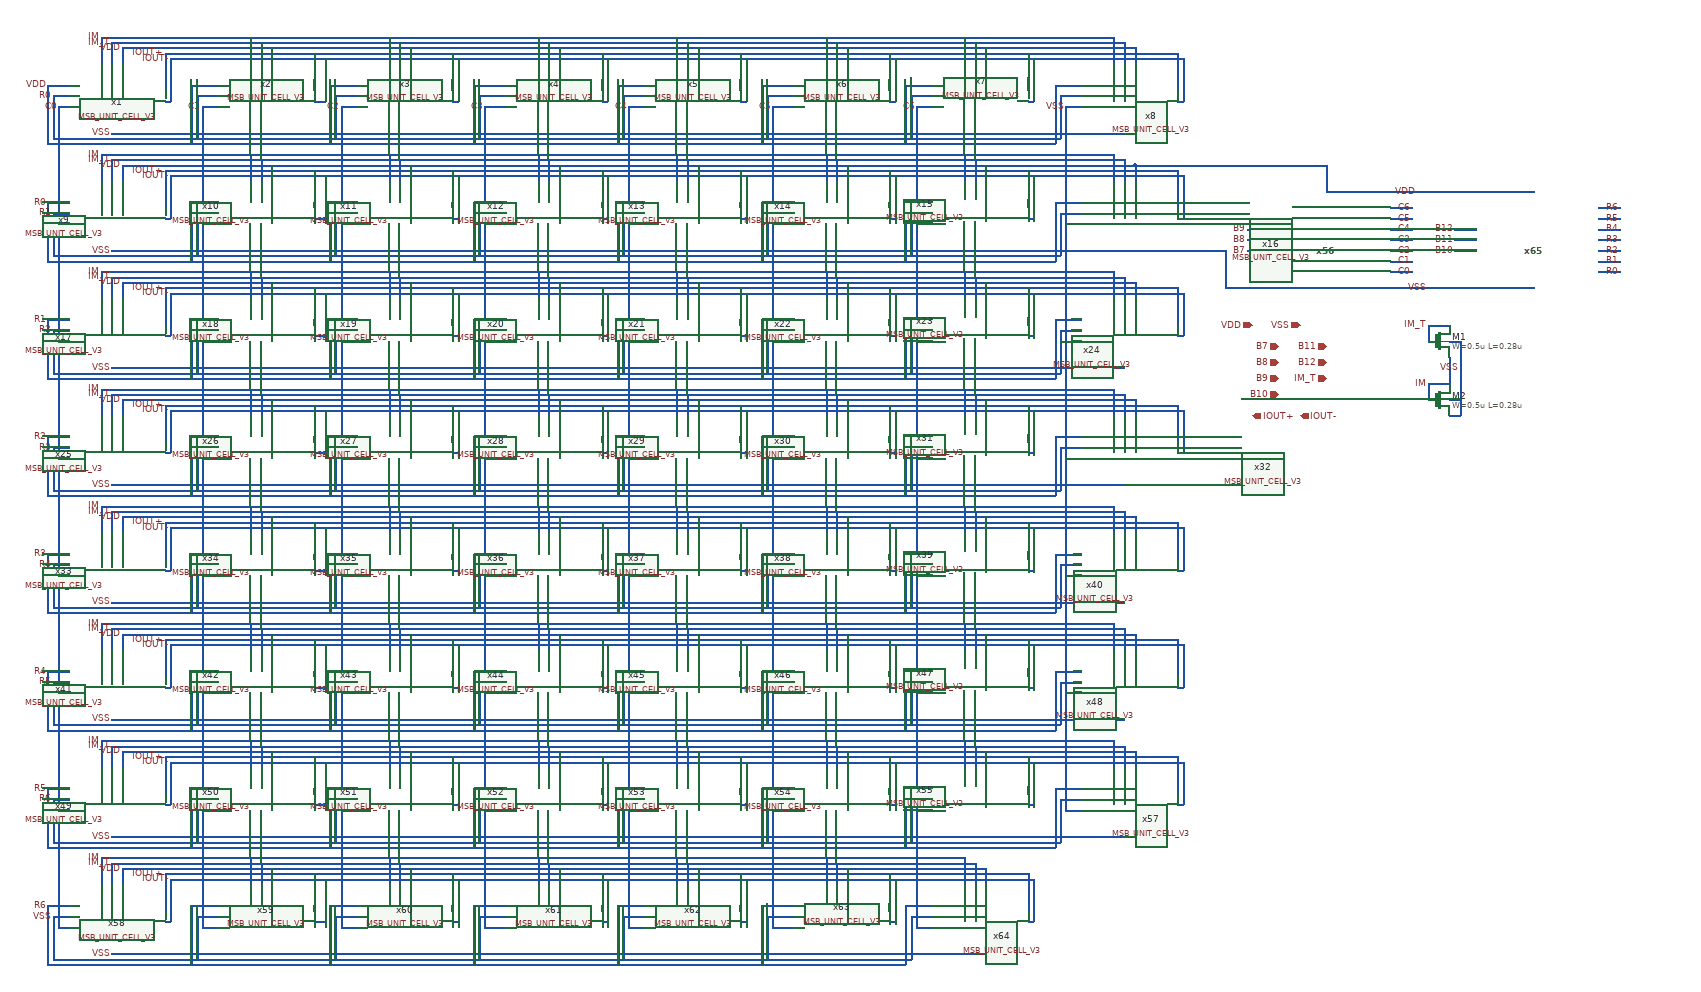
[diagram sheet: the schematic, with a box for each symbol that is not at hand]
v {xschem version=3.1.0 file_version=1.2
}
G {}
K {}
V {}
S {}
E {}
N 210 -1780 210 -1730 {
lab=IM}
N 210 -1780 2110 -1780 {
lab=IM}
N 2110 -1780 2110 -1730 {
lab=IM}
N 2130 -1770 2130 -1730 {
lab=IM_T}
N 2120 -1770 2130 -1770 {
lab=IM_T}
N 230 -1770 2120 -1770 {
lab=IM_T}
N 230 -1770 230 -1730 {
lab=IM_T}
N 250 -1760 250 -1730 {
lab=VDD}
N 250 -1760 2150 -1760 {
lab=VDD}
N 2150 -1760 2150 -1730 {
lab=VDD}
N 2230 -1750 2230 -1680 {
lab=IOUT+}
N 330 -1750 2230 -1750 {
lab=IOUT+}
N 330 -1750 330 -1680 {
lab=IOUT+}
N 330 -1660 340 -1660 {
lab=IOUT-}
N 340 -1740 340 -1660 {
lab=IOUT-}
N 340 -1740 2240 -1740 {
lab=IOUT-}
N 2240 -1740 2240 -1660 {
lab=IOUT-}
N 2230 -1660 2240 -1660 {
lab=IOUT-}
N 230 -1600 2130 -1600 {
lab=VSS}
N 490 -1780 490 -1730 {
lab=IM}
N 510 -1770 510 -1730 {
lab=IM_T}
N 530 -1760 530 -1730 {
lab=VDD}
N 610 -1750 610 -1680 {
lab=IOUT+}
N 610 -1660 630 -1660 {
lab=IOUT-}
N 630 -1740 630 -1660 {
lab=IOUT-}
N 750 -1780 750 -1730 {
lab=IM}
N 770 -1770 770 -1730 {
lab=IM_T}
N 790 -1760 790 -1730 {
lab=VDD}
N 870 -1750 870 -1680 {
lab=IOUT+}
N 880 -1740 880 -1660 {
lab=IOUT-}
N 870 -1660 880 -1660 {
lab=IOUT-}
N 1030 -1780 1030 -1730 {
lab=IM}
N 1050 -1770 1050 -1730 {
lab=IM_T}
N 1070 -1760 1070 -1730 {
lab=VDD}
N 1150 -1750 1150 -1680 {
lab=IOUT+}
N 1150 -1660 1160 -1660 {
lab=IOUT-}
N 1160 -1740 1160 -1660 {
lab=IOUT-}
N 1290 -1780 1290 -1730 {
lab=IM}
N 1310 -1770 1310 -1730 {
lab=IM_T}
N 1330 -1760 1330 -1730 {
lab=VDD}
N 1410 -1750 1410 -1680 {
lab=IOUT+}
N 1420 -1740 1420 -1660 {
lab=IOUT-}
N 1410 -1660 1420 -1660 {
lab=IOUT-}
N 1570 -1780 1570 -1730 {
lab=IM}
N 1590 -1770 1590 -1730 {
lab=IM_T}
N 1610 -1760 1610 -1730 {
lab=VDD}
N 1690 -1750 1690 -1680 {
lab=IOUT+}
N 1700 -1740 1700 -1660 {
lab=IOUT-}
N 1690 -1660 1700 -1660 {
lab=IOUT-}
N 1830 -1780 1830 -1730 {
lab=IM}
N 1850 -1770 1850 -1730 {
lab=IM_T}
N 1870 -1760 1870 -1730 {
lab=VDD}
N 1950 -1750 1950 -1680 {
lab=IOUT+}
N 1950 -1660 1960 -1660 {
lab=IOUT-}
N 1960 -1740 1960 -1660 {
lab=IOUT-}
N 120 -1670 150 -1670 {
lab=R0}
N 120 -1670 120 -1590 {
lab=R0}
N 120 -1590 2010 -1590 {
lab=R0}
N 2010 -1670 2010 -1590 {
lab=R0}
N 2010 -1670 2050 -1670 {
lab=R0}
N 2000 -1690 2050 -1690 {
lab=VDD}
N 2000 -1690 2000 -1580 {
lab=VDD}
N 110 -1580 2000 -1580 {
lab=VDD}
N 110 -1690 110 -1580 {
lab=VDD}
N 110 -1690 150 -1690 {
lab=VDD}
N 380 -1690 430 -1690 {
lab=VDD}
N 380 -1690 380 -1580 {
lab=VDD}
N 390 -1670 390 -1590 {
lab=R0}
N 390 -1670 430 -1670 {
lab=R0}
N 640 -1690 690 -1690 {
lab=VDD}
N 640 -1690 640 -1580 {
lab=VDD}
N 650 -1670 690 -1670 {
lab=R0}
N 650 -1670 650 -1590 {
lab=R0}
N 910 -1690 970 -1690 {
lab=VDD}
N 910 -1690 910 -1580 {
lab=VDD}
N 920 -1670 970 -1670 {
lab=R0}
N 920 -1670 920 -1590 {
lab=R0}
N 1180 -1690 1230 -1690 {
lab=VDD}
N 1180 -1690 1180 -1580 {
lab=VDD}
N 1190 -1670 1230 -1670 {
lab=R0}
N 1190 -1670 1190 -1590 {
lab=R0}
N 1450 -1690 1510 -1690 {
lab=VDD}
N 1450 -1690 1450 -1580 {
lab=VDD}
N 1460 -1670 1510 -1670 {
lab=R0}
N 1460 -1670 1460 -1590 {
lab=R0}
N 1720 -1690 1770 -1690 {
lab=VDD}
N 1720 -1690 1720 -1580 {
lab=VDD}
N 1730 -1670 1770 -1670 {
lab=R0}
N 1730 -1670 1730 -1590 {
lab=R0}
N 210 -1560 210 -1510 {
lab=IM}
N 210 -1560 2110 -1560 {
lab=IM}
N 2110 -1560 2110 -1510 {
lab=IM}
N 2130 -1550 2130 -1510 {
lab=IM_T}
N 2120 -1550 2130 -1550 {
lab=IM_T}
N 230 -1550 2120 -1550 {
lab=IM_T}
N 230 -1550 230 -1510 {
lab=IM_T}
N 250 -1540 250 -1510 {
lab=VDD}
N 250 -1540 2150 -1540 {
lab=VDD}
N 2150 -1540 2150 -1510 {
lab=VDD}
N 2230 -1530 2230 -1460 {
lab=IOUT+}
N 330 -1530 2230 -1530 {
lab=IOUT+}
N 330 -1530 330 -1460 {
lab=IOUT+}
N 330 -1440 340 -1440 {
lab=IOUT-}
N 340 -1520 340 -1440 {
lab=IOUT-}
N 340 -1520 2240 -1520 {
lab=IOUT-}
N 2240 -1520 2240 -1440 {
lab=IOUT-}
N 2230 -1440 2240 -1440 {
lab=IOUT-}
N 230 -1380 2130 -1380 {
lab=VSS}
N 490 -1560 490 -1510 {
lab=IM}
N 510 -1550 510 -1510 {
lab=IM_T}
N 530 -1540 530 -1510 {
lab=VDD}
N 610 -1530 610 -1460 {
lab=IOUT+}
N 610 -1440 630 -1440 {
lab=IOUT-}
N 630 -1520 630 -1440 {
lab=IOUT-}
N 750 -1560 750 -1510 {
lab=IM}
N 770 -1550 770 -1510 {
lab=IM_T}
N 790 -1540 790 -1510 {
lab=VDD}
N 870 -1530 870 -1460 {
lab=IOUT+}
N 880 -1520 880 -1440 {
lab=IOUT-}
N 870 -1440 880 -1440 {
lab=IOUT-}
N 1030 -1560 1030 -1510 {
lab=IM}
N 1050 -1550 1050 -1510 {
lab=IM_T}
N 1070 -1540 1070 -1510 {
lab=VDD}
N 1150 -1530 1150 -1460 {
lab=IOUT+}
N 1150 -1440 1160 -1440 {
lab=IOUT-}
N 1160 -1520 1160 -1440 {
lab=IOUT-}
N 1290 -1560 1290 -1510 {
lab=IM}
N 1310 -1550 1310 -1510 {
lab=IM_T}
N 1330 -1540 1330 -1510 {
lab=VDD}
N 1410 -1530 1410 -1460 {
lab=IOUT+}
N 1420 -1520 1420 -1440 {
lab=IOUT-}
N 1410 -1440 1420 -1440 {
lab=IOUT-}
N 1570 -1560 1570 -1510 {
lab=IM}
N 1590 -1550 1590 -1510 {
lab=IM_T}
N 1610 -1540 1610 -1510 {
lab=VDD}
N 1690 -1530 1690 -1460 {
lab=IOUT+}
N 1700 -1520 1700 -1440 {
lab=IOUT-}
N 1690 -1440 1700 -1440 {
lab=IOUT-}
N 1830 -1560 1830 -1510 {
lab=IM}
N 1850 -1550 1850 -1510 {
lab=IM_T}
N 1870 -1540 1870 -1510 {
lab=VDD}
N 1950 -1530 1950 -1460 {
lab=IOUT+}
N 1950 -1440 1960 -1440 {
lab=IOUT-}
N 1960 -1520 1960 -1440 {
lab=IOUT-}
N 120 -1450 150 -1450 {
lab=R1}
N 120 -1450 120 -1370 {
lab=R1}
N 120 -1370 2010 -1370 {
lab=R1}
N 2010 -1450 2010 -1370 {
lab=R1}
N 2010 -1450 2050 -1450 {
lab=R1}
N 2000 -1470 2050 -1470 {
lab=R0}
N 2000 -1470 2000 -1360 {
lab=R0}
N 110 -1360 2000 -1360 {
lab=R0}
N 110 -1470 110 -1360 {
lab=R0}
N 110 -1470 150 -1470 {
lab=R0}
N 380 -1470 430 -1470 {
lab=R0}
N 380 -1470 380 -1360 {
lab=R0}
N 390 -1450 390 -1370 {
lab=R1}
N 390 -1450 430 -1450 {
lab=R1}
N 640 -1470 690 -1470 {
lab=R0}
N 640 -1470 640 -1360 {
lab=R0}
N 650 -1450 690 -1450 {
lab=R1}
N 650 -1450 650 -1370 {
lab=R1}
N 910 -1470 970 -1470 {
lab=R0}
N 910 -1470 910 -1360 {
lab=R0}
N 920 -1450 970 -1450 {
lab=R1}
N 920 -1450 920 -1370 {
lab=R1}
N 1180 -1470 1230 -1470 {
lab=R0}
N 1180 -1470 1180 -1360 {
lab=R0}
N 1190 -1450 1230 -1450 {
lab=R1}
N 1190 -1450 1190 -1370 {
lab=R1}
N 1450 -1470 1510 -1470 {
lab=R0}
N 1450 -1470 1450 -1360 {
lab=R0}
N 1460 -1450 1510 -1450 {
lab=R1}
N 1460 -1450 1460 -1370 {
lab=R1}
N 1720 -1470 1770 -1470 {
lab=R0}
N 1720 -1470 1720 -1360 {
lab=R0}
N 1730 -1450 1770 -1450 {
lab=R1}
N 1730 -1450 1730 -1370 {
lab=R1}
N 210 -1340 210 -1290 {
lab=IM}
N 210 -1340 2110 -1340 {
lab=IM}
N 2110 -1340 2110 -1290 {
lab=IM}
N 2130 -1330 2130 -1290 {
lab=IM_T}
N 2120 -1330 2130 -1330 {
lab=IM_T}
N 230 -1330 2120 -1330 {
lab=IM_T}
N 230 -1330 230 -1290 {
lab=IM_T}
N 250 -1320 250 -1290 {
lab=VDD}
N 250 -1320 2150 -1320 {
lab=VDD}
N 2150 -1320 2150 -1290 {
lab=VDD}
N 2230 -1310 2230 -1240 {
lab=IOUT+}
N 330 -1310 2230 -1310 {
lab=IOUT+}
N 330 -1310 330 -1240 {
lab=IOUT+}
N 330 -1220 340 -1220 {
lab=IOUT-}
N 340 -1300 340 -1220 {
lab=IOUT-}
N 340 -1300 2240 -1300 {
lab=IOUT-}
N 2240 -1300 2240 -1220 {
lab=IOUT-}
N 2230 -1220 2240 -1220 {
lab=IOUT-}
N 230 -1160 2130 -1160 {
lab=VSS}
N 490 -1340 490 -1290 {
lab=IM}
N 510 -1330 510 -1290 {
lab=IM_T}
N 530 -1320 530 -1290 {
lab=VDD}
N 610 -1310 610 -1240 {
lab=IOUT+}
N 610 -1220 630 -1220 {
lab=IOUT-}
N 630 -1300 630 -1220 {
lab=IOUT-}
N 750 -1340 750 -1290 {
lab=IM}
N 770 -1330 770 -1290 {
lab=IM_T}
N 790 -1320 790 -1290 {
lab=VDD}
N 870 -1310 870 -1240 {
lab=IOUT+}
N 880 -1300 880 -1220 {
lab=IOUT-}
N 870 -1220 880 -1220 {
lab=IOUT-}
N 1030 -1340 1030 -1290 {
lab=IM}
N 1050 -1330 1050 -1290 {
lab=IM_T}
N 1070 -1320 1070 -1290 {
lab=VDD}
N 1150 -1310 1150 -1240 {
lab=IOUT+}
N 1150 -1220 1160 -1220 {
lab=IOUT-}
N 1160 -1300 1160 -1220 {
lab=IOUT-}
N 1290 -1340 1290 -1290 {
lab=IM}
N 1310 -1330 1310 -1290 {
lab=IM_T}
N 1330 -1320 1330 -1290 {
lab=VDD}
N 1410 -1310 1410 -1240 {
lab=IOUT+}
N 1420 -1300 1420 -1220 {
lab=IOUT-}
N 1410 -1220 1420 -1220 {
lab=IOUT-}
N 1570 -1340 1570 -1290 {
lab=IM}
N 1590 -1330 1590 -1290 {
lab=IM_T}
N 1610 -1320 1610 -1290 {
lab=VDD}
N 1690 -1310 1690 -1240 {
lab=IOUT+}
N 1700 -1300 1700 -1220 {
lab=IOUT-}
N 1690 -1220 1700 -1220 {
lab=IOUT-}
N 1830 -1340 1830 -1290 {
lab=IM}
N 1850 -1330 1850 -1290 {
lab=IM_T}
N 1870 -1320 1870 -1290 {
lab=VDD}
N 1950 -1310 1950 -1240 {
lab=IOUT+}
N 1950 -1220 1960 -1220 {
lab=IOUT-}
N 1960 -1300 1960 -1220 {
lab=IOUT-}
N 120 -1230 150 -1230 {
lab=R2}
N 120 -1230 120 -1150 {
lab=R2}
N 120 -1150 2010 -1150 {
lab=R2}
N 2010 -1230 2010 -1150 {
lab=R2}
N 2010 -1230 2050 -1230 {
lab=R2}
N 2000 -1250 2050 -1250 {
lab=R1}
N 2000 -1250 2000 -1140 {
lab=R1}
N 110 -1140 2000 -1140 {
lab=R1}
N 110 -1250 110 -1140 {
lab=R1}
N 110 -1250 150 -1250 {
lab=R1}
N 380 -1250 430 -1250 {
lab=R1}
N 380 -1250 380 -1140 {
lab=R1}
N 390 -1230 390 -1150 {
lab=R2}
N 390 -1230 430 -1230 {
lab=R2}
N 640 -1250 690 -1250 {
lab=R1}
N 640 -1250 640 -1140 {
lab=R1}
N 650 -1230 690 -1230 {
lab=R2}
N 650 -1230 650 -1150 {
lab=R2}
N 910 -1250 970 -1250 {
lab=R1}
N 910 -1250 910 -1140 {
lab=R1}
N 920 -1230 970 -1230 {
lab=R2}
N 920 -1230 920 -1150 {
lab=R2}
N 1180 -1250 1230 -1250 {
lab=R1}
N 1180 -1250 1180 -1140 {
lab=R1}
N 1190 -1230 1230 -1230 {
lab=R2}
N 1190 -1230 1190 -1150 {
lab=R2}
N 1450 -1250 1510 -1250 {
lab=R1}
N 1450 -1250 1450 -1140 {
lab=R1}
N 1460 -1230 1510 -1230 {
lab=R2}
N 1460 -1230 1460 -1150 {
lab=R2}
N 1720 -1250 1770 -1250 {
lab=R1}
N 1720 -1250 1720 -1140 {
lab=R1}
N 1730 -1230 1770 -1230 {
lab=R2}
N 1730 -1230 1730 -1150 {
lab=R2}
N 210 -1120 210 -1070 {
lab=IM}
N 210 -1120 2110 -1120 {
lab=IM}
N 2110 -1120 2110 -1070 {
lab=IM}
N 2130 -1110 2130 -1070 {
lab=IM_T}
N 2120 -1110 2130 -1110 {
lab=IM_T}
N 230 -1110 2120 -1110 {
lab=IM_T}
N 230 -1110 230 -1070 {
lab=IM_T}
N 250 -1100 250 -1070 {
lab=VDD}
N 250 -1100 2150 -1100 {
lab=VDD}
N 2150 -1100 2150 -1070 {
lab=VDD}
N 2230 -1090 2230 -1020 {
lab=IOUT+}
N 330 -1090 2230 -1090 {
lab=IOUT+}
N 330 -1090 330 -1020 {
lab=IOUT+}
N 330 -1000 340 -1000 {
lab=IOUT-}
N 340 -1080 340 -1000 {
lab=IOUT-}
N 340 -1080 2240 -1080 {
lab=IOUT-}
N 2240 -1080 2240 -1000 {
lab=IOUT-}
N 2230 -1000 2240 -1000 {
lab=IOUT-}
N 230 -940 2130 -940 {
lab=VSS}
N 490 -1120 490 -1070 {
lab=IM}
N 510 -1110 510 -1070 {
lab=IM_T}
N 530 -1100 530 -1070 {
lab=VDD}
N 610 -1090 610 -1020 {
lab=IOUT+}
N 610 -1000 630 -1000 {
lab=IOUT-}
N 630 -1080 630 -1000 {
lab=IOUT-}
N 750 -1120 750 -1070 {
lab=IM}
N 770 -1110 770 -1070 {
lab=IM_T}
N 790 -1100 790 -1070 {
lab=VDD}
N 870 -1090 870 -1020 {
lab=IOUT+}
N 880 -1080 880 -1000 {
lab=IOUT-}
N 870 -1000 880 -1000 {
lab=IOUT-}
N 1030 -1120 1030 -1070 {
lab=IM}
N 1050 -1110 1050 -1070 {
lab=IM_T}
N 1070 -1100 1070 -1070 {
lab=VDD}
N 1150 -1090 1150 -1020 {
lab=IOUT+}
N 1150 -1000 1160 -1000 {
lab=IOUT-}
N 1160 -1080 1160 -1000 {
lab=IOUT-}
N 1290 -1120 1290 -1070 {
lab=IM}
N 1310 -1110 1310 -1070 {
lab=IM_T}
N 1330 -1100 1330 -1070 {
lab=VDD}
N 1410 -1090 1410 -1020 {
lab=IOUT+}
N 1420 -1080 1420 -1000 {
lab=IOUT-}
N 1410 -1000 1420 -1000 {
lab=IOUT-}
N 1570 -1120 1570 -1070 {
lab=IM}
N 1590 -1110 1590 -1070 {
lab=IM_T}
N 1610 -1100 1610 -1070 {
lab=VDD}
N 1690 -1090 1690 -1020 {
lab=IOUT+}
N 1700 -1080 1700 -1000 {
lab=IOUT-}
N 1690 -1000 1700 -1000 {
lab=IOUT-}
N 1830 -1120 1830 -1070 {
lab=IM}
N 1850 -1110 1850 -1070 {
lab=IM_T}
N 1870 -1100 1870 -1070 {
lab=VDD}
N 1950 -1090 1950 -1020 {
lab=IOUT+}
N 1950 -1000 1960 -1000 {
lab=IOUT-}
N 1960 -1080 1960 -1000 {
lab=IOUT-}
N 120 -1010 150 -1010 {
lab=R3}
N 120 -1010 120 -930 {
lab=R3}
N 120 -930 2010 -930 {
lab=R3}
N 2010 -1010 2010 -930 {
lab=R3}
N 2010 -1010 2050 -1010 {
lab=R3}
N 2000 -1030 2050 -1030 {
lab=R2}
N 2000 -1030 2000 -920 {
lab=R2}
N 110 -920 2000 -920 {
lab=R2}
N 110 -1030 110 -920 {
lab=R2}
N 110 -1030 150 -1030 {
lab=R2}
N 380 -1030 430 -1030 {
lab=R2}
N 380 -1030 380 -920 {
lab=R2}
N 390 -1010 390 -930 {
lab=R3}
N 390 -1010 430 -1010 {
lab=R3}
N 640 -1030 690 -1030 {
lab=R2}
N 640 -1030 640 -920 {
lab=R2}
N 650 -1010 690 -1010 {
lab=R3}
N 650 -1010 650 -930 {
lab=R3}
N 910 -1030 970 -1030 {
lab=R2}
N 910 -1030 910 -920 {
lab=R2}
N 920 -1010 970 -1010 {
lab=R3}
N 920 -1010 920 -930 {
lab=R3}
N 1180 -1030 1230 -1030 {
lab=R2}
N 1180 -1030 1180 -920 {
lab=R2}
N 1190 -1010 1230 -1010 {
lab=R3}
N 1190 -1010 1190 -930 {
lab=R3}
N 1450 -1030 1510 -1030 {
lab=R2}
N 1450 -1030 1450 -920 {
lab=R2}
N 1460 -1010 1510 -1010 {
lab=R3}
N 1460 -1010 1460 -930 {
lab=R3}
N 1720 -1030 1770 -1030 {
lab=R2}
N 1720 -1030 1720 -920 {
lab=R2}
N 1730 -1010 1770 -1010 {
lab=R3}
N 1730 -1010 1730 -930 {
lab=R3}
N 210 -900 210 -850 {
lab=IM}
N 210 -900 2110 -900 {
lab=IM}
N 2110 -900 2110 -850 {
lab=IM}
N 2130 -890 2130 -850 {
lab=IM_T}
N 2120 -890 2130 -890 {
lab=IM_T}
N 230 -890 2120 -890 {
lab=IM_T}
N 230 -890 230 -850 {
lab=IM_T}
N 250 -880 250 -850 {
lab=VDD}
N 250 -880 2150 -880 {
lab=VDD}
N 2150 -880 2150 -850 {
lab=VDD}
N 2230 -870 2230 -800 {
lab=IOUT+}
N 330 -870 2230 -870 {
lab=IOUT+}
N 330 -870 330 -800 {
lab=IOUT+}
N 330 -780 340 -780 {
lab=IOUT-}
N 340 -860 340 -780 {
lab=IOUT-}
N 340 -860 2240 -860 {
lab=IOUT-}
N 2240 -860 2240 -780 {
lab=IOUT-}
N 2230 -780 2240 -780 {
lab=IOUT-}
N 230 -720 2130 -720 {
lab=VSS}
N 490 -900 490 -850 {
lab=IM}
N 510 -890 510 -850 {
lab=IM_T}
N 530 -880 530 -850 {
lab=VDD}
N 610 -870 610 -800 {
lab=IOUT+}
N 610 -780 630 -780 {
lab=IOUT-}
N 630 -860 630 -780 {
lab=IOUT-}
N 750 -900 750 -850 {
lab=IM}
N 770 -890 770 -850 {
lab=IM_T}
N 790 -880 790 -850 {
lab=VDD}
N 870 -870 870 -800 {
lab=IOUT+}
N 880 -860 880 -780 {
lab=IOUT-}
N 870 -780 880 -780 {
lab=IOUT-}
N 1030 -900 1030 -850 {
lab=IM}
N 1050 -890 1050 -850 {
lab=IM_T}
N 1070 -880 1070 -850 {
lab=VDD}
N 1150 -870 1150 -800 {
lab=IOUT+}
N 1150 -780 1160 -780 {
lab=IOUT-}
N 1160 -860 1160 -780 {
lab=IOUT-}
N 1290 -900 1290 -850 {
lab=IM}
N 1310 -890 1310 -850 {
lab=IM_T}
N 1330 -880 1330 -850 {
lab=VDD}
N 1410 -870 1410 -800 {
lab=IOUT+}
N 1420 -860 1420 -780 {
lab=IOUT-}
N 1410 -780 1420 -780 {
lab=IOUT-}
N 1570 -900 1570 -850 {
lab=IM}
N 1590 -890 1590 -850 {
lab=IM_T}
N 1610 -880 1610 -850 {
lab=VDD}
N 1690 -870 1690 -800 {
lab=IOUT+}
N 1700 -860 1700 -780 {
lab=IOUT-}
N 1690 -780 1700 -780 {
lab=IOUT-}
N 1830 -900 1830 -850 {
lab=IM}
N 1850 -890 1850 -850 {
lab=IM_T}
N 1870 -880 1870 -850 {
lab=VDD}
N 1950 -870 1950 -800 {
lab=IOUT+}
N 1950 -780 1960 -780 {
lab=IOUT-}
N 1960 -860 1960 -780 {
lab=IOUT-}
N 120 -790 150 -790 {
lab=R4}
N 120 -790 120 -710 {
lab=R4}
N 120 -710 2010 -710 {
lab=R4}
N 2010 -790 2010 -710 {
lab=R4}
N 2010 -790 2050 -790 {
lab=R4}
N 2000 -810 2050 -810 {
lab=R3}
N 2000 -810 2000 -700 {
lab=R3}
N 110 -700 2000 -700 {
lab=R3}
N 110 -810 110 -700 {
lab=R3}
N 110 -810 150 -810 {
lab=R3}
N 380 -810 430 -810 {
lab=R3}
N 380 -810 380 -700 {
lab=R3}
N 390 -790 390 -710 {
lab=R4}
N 390 -790 430 -790 {
lab=R4}
N 640 -810 690 -810 {
lab=R3}
N 640 -810 640 -700 {
lab=R3}
N 650 -790 690 -790 {
lab=R4}
N 650 -790 650 -710 {
lab=R4}
N 910 -810 970 -810 {
lab=R3}
N 910 -810 910 -700 {
lab=R3}
N 920 -790 970 -790 {
lab=R4}
N 920 -790 920 -710 {
lab=R4}
N 1180 -810 1230 -810 {
lab=R3}
N 1180 -810 1180 -700 {
lab=R3}
N 1190 -790 1230 -790 {
lab=R4}
N 1190 -790 1190 -710 {
lab=R4}
N 1450 -810 1510 -810 {
lab=R3}
N 1450 -810 1450 -700 {
lab=R3}
N 1460 -790 1510 -790 {
lab=R4}
N 1460 -790 1460 -710 {
lab=R4}
N 1720 -810 1770 -810 {
lab=R3}
N 1720 -810 1720 -700 {
lab=R3}
N 1730 -790 1770 -790 {
lab=R4}
N 1730 -790 1730 -710 {
lab=R4}
N 210 -680 210 -630 {
lab=IM}
N 210 -680 2110 -680 {
lab=IM}
N 2110 -680 2110 -630 {
lab=IM}
N 2130 -670 2130 -630 {
lab=IM_T}
N 2120 -670 2130 -670 {
lab=IM_T}
N 230 -670 2120 -670 {
lab=IM_T}
N 230 -670 230 -630 {
lab=IM_T}
N 250 -660 250 -630 {
lab=VDD}
N 250 -660 2150 -660 {
lab=VDD}
N 2150 -660 2150 -630 {
lab=VDD}
N 2230 -650 2230 -580 {
lab=IOUT+}
N 330 -650 2230 -650 {
lab=IOUT+}
N 330 -650 330 -580 {
lab=IOUT+}
N 330 -560 340 -560 {
lab=IOUT-}
N 340 -640 340 -560 {
lab=IOUT-}
N 340 -640 2240 -640 {
lab=IOUT-}
N 2240 -640 2240 -560 {
lab=IOUT-}
N 2230 -560 2240 -560 {
lab=IOUT-}
N 230 -500 2130 -500 {
lab=VSS}
N 490 -680 490 -630 {
lab=IM}
N 510 -670 510 -630 {
lab=IM_T}
N 530 -660 530 -630 {
lab=VDD}
N 610 -650 610 -580 {
lab=IOUT+}
N 610 -560 630 -560 {
lab=IOUT-}
N 630 -640 630 -560 {
lab=IOUT-}
N 750 -680 750 -630 {
lab=IM}
N 770 -670 770 -630 {
lab=IM_T}
N 790 -660 790 -630 {
lab=VDD}
N 870 -650 870 -580 {
lab=IOUT+}
N 880 -640 880 -560 {
lab=IOUT-}
N 870 -560 880 -560 {
lab=IOUT-}
N 1030 -680 1030 -630 {
lab=IM}
N 1050 -670 1050 -630 {
lab=IM_T}
N 1070 -660 1070 -630 {
lab=VDD}
N 1150 -650 1150 -580 {
lab=IOUT+}
N 1150 -560 1160 -560 {
lab=IOUT-}
N 1160 -640 1160 -560 {
lab=IOUT-}
N 1290 -680 1290 -630 {
lab=IM}
N 1310 -670 1310 -630 {
lab=IM_T}
N 1330 -660 1330 -630 {
lab=VDD}
N 1410 -650 1410 -580 {
lab=IOUT+}
N 1420 -640 1420 -560 {
lab=IOUT-}
N 1410 -560 1420 -560 {
lab=IOUT-}
N 1570 -680 1570 -630 {
lab=IM}
N 1590 -670 1590 -630 {
lab=IM_T}
N 1610 -660 1610 -630 {
lab=VDD}
N 1690 -650 1690 -580 {
lab=IOUT+}
N 1700 -640 1700 -560 {
lab=IOUT-}
N 1690 -560 1700 -560 {
lab=IOUT-}
N 1830 -680 1830 -630 {
lab=IM}
N 1850 -670 1850 -630 {
lab=IM_T}
N 1870 -660 1870 -630 {
lab=VDD}
N 1950 -650 1950 -580 {
lab=IOUT+}
N 1950 -560 1960 -560 {
lab=IOUT-}
N 1960 -640 1960 -560 {
lab=IOUT-}
N 120 -570 150 -570 {
lab=R5}
N 120 -570 120 -490 {
lab=R5}
N 120 -490 2010 -490 {
lab=R5}
N 2010 -570 2010 -490 {
lab=R5}
N 2010 -570 2050 -570 {
lab=R5}
N 2000 -590 2050 -590 {
lab=R4}
N 2000 -590 2000 -480 {
lab=R4}
N 110 -480 2000 -480 {
lab=R4}
N 110 -590 110 -480 {
lab=R4}
N 110 -590 150 -590 {
lab=R4}
N 380 -590 430 -590 {
lab=R4}
N 380 -590 380 -480 {
lab=R4}
N 390 -570 390 -490 {
lab=R5}
N 390 -570 430 -570 {
lab=R5}
N 640 -590 690 -590 {
lab=R4}
N 640 -590 640 -480 {
lab=R4}
N 650 -570 690 -570 {
lab=R5}
N 650 -570 650 -490 {
lab=R5}
N 910 -590 970 -590 {
lab=R4}
N 910 -590 910 -480 {
lab=R4}
N 920 -570 970 -570 {
lab=R5}
N 920 -570 920 -490 {
lab=R5}
N 1180 -590 1230 -590 {
lab=R4}
N 1180 -590 1180 -480 {
lab=R4}
N 1190 -570 1230 -570 {
lab=R5}
N 1190 -570 1190 -490 {
lab=R5}
N 1450 -590 1510 -590 {
lab=R4}
N 1450 -590 1450 -480 {
lab=R4}
N 1460 -570 1510 -570 {
lab=R5}
N 1460 -570 1460 -490 {
lab=R5}
N 1720 -590 1770 -590 {
lab=R4}
N 1720 -590 1720 -480 {
lab=R4}
N 1730 -570 1770 -570 {
lab=R5}
N 1730 -570 1730 -490 {
lab=R5}
N 210 -460 210 -410 {
lab=IM}
N 210 -460 2110 -460 {
lab=IM}
N 2110 -460 2110 -410 {
lab=IM}
N 2130 -450 2130 -410 {
lab=IM_T}
N 2120 -450 2130 -450 {
lab=IM_T}
N 230 -450 2120 -450 {
lab=IM_T}
N 230 -450 230 -410 {
lab=IM_T}
N 250 -440 250 -410 {
lab=VDD}
N 250 -440 2150 -440 {
lab=VDD}
N 2150 -440 2150 -410 {
lab=VDD}
N 2230 -430 2230 -360 {
lab=IOUT+}
N 330 -430 2230 -430 {
lab=IOUT+}
N 330 -430 330 -360 {
lab=IOUT+}
N 330 -340 340 -340 {
lab=IOUT-}
N 340 -420 340 -340 {
lab=IOUT-}
N 340 -420 2240 -420 {
lab=IOUT-}
N 2240 -420 2240 -340 {
lab=IOUT-}
N 2230 -340 2240 -340 {
lab=IOUT-}
N 230 -280 2130 -280 {
lab=VSS}
N 490 -460 490 -410 {
lab=IM}
N 510 -450 510 -410 {
lab=IM_T}
N 530 -440 530 -410 {
lab=VDD}
N 610 -430 610 -360 {
lab=IOUT+}
N 610 -340 630 -340 {
lab=IOUT-}
N 630 -420 630 -340 {
lab=IOUT-}
N 750 -460 750 -410 {
lab=IM}
N 770 -450 770 -410 {
lab=IM_T}
N 790 -440 790 -410 {
lab=VDD}
N 870 -430 870 -360 {
lab=IOUT+}
N 880 -420 880 -340 {
lab=IOUT-}
N 870 -340 880 -340 {
lab=IOUT-}
N 1030 -460 1030 -410 {
lab=IM}
N 1050 -450 1050 -410 {
lab=IM_T}
N 1070 -440 1070 -410 {
lab=VDD}
N 1150 -430 1150 -360 {
lab=IOUT+}
N 1150 -340 1160 -340 {
lab=IOUT-}
N 1160 -420 1160 -340 {
lab=IOUT-}
N 1290 -460 1290 -410 {
lab=IM}
N 1310 -450 1310 -410 {
lab=IM_T}
N 1330 -440 1330 -410 {
lab=VDD}
N 1410 -430 1410 -360 {
lab=IOUT+}
N 1420 -420 1420 -340 {
lab=IOUT-}
N 1410 -340 1420 -340 {
lab=IOUT-}
N 1570 -460 1570 -410 {
lab=IM}
N 1590 -450 1590 -410 {
lab=IM_T}
N 1610 -440 1610 -410 {
lab=VDD}
N 1690 -430 1690 -360 {
lab=IOUT+}
N 1700 -420 1700 -340 {
lab=IOUT-}
N 1690 -340 1700 -340 {
lab=IOUT-}
N 1830 -460 1830 -410 {
lab=IM}
N 1850 -450 1850 -410 {
lab=IM_T}
N 1870 -440 1870 -410 {
lab=VDD}
N 1950 -430 1950 -360 {
lab=IOUT+}
N 1950 -340 1960 -340 {
lab=IOUT-}
N 1960 -420 1960 -340 {
lab=IOUT-}
N 120 -350 150 -350 {
lab=R6}
N 120 -350 120 -270 {
lab=R6}
N 120 -270 2010 -270 {
lab=R6}
N 2010 -350 2010 -270 {
lab=R6}
N 2010 -350 2050 -350 {
lab=R6}
N 2000 -370 2050 -370 {
lab=R5}
N 2000 -370 2000 -260 {
lab=R5}
N 110 -260 2000 -260 {
lab=R5}
N 110 -370 110 -260 {
lab=R5}
N 110 -370 150 -370 {
lab=R5}
N 380 -370 430 -370 {
lab=R5}
N 380 -370 380 -260 {
lab=R5}
N 390 -350 390 -270 {
lab=R6}
N 390 -350 430 -350 {
lab=R6}
N 640 -370 690 -370 {
lab=R5}
N 640 -370 640 -260 {
lab=R5}
N 650 -350 690 -350 {
lab=R6}
N 650 -350 650 -270 {
lab=R6}
N 910 -370 970 -370 {
lab=R5}
N 910 -370 910 -260 {
lab=R5}
N 920 -350 970 -350 {
lab=R6}
N 920 -350 920 -270 {
lab=R6}
N 1180 -370 1230 -370 {
lab=R5}
N 1180 -370 1180 -260 {
lab=R5}
N 1190 -350 1230 -350 {
lab=R6}
N 1190 -350 1190 -270 {
lab=R6}
N 1450 -370 1510 -370 {
lab=R5}
N 1450 -370 1450 -260 {
lab=R5}
N 1460 -350 1510 -350 {
lab=R6}
N 1460 -350 1460 -270 {
lab=R6}
N 1720 -370 1770 -370 {
lab=R5}
N 1720 -370 1720 -260 {
lab=R5}
N 1730 -350 1770 -350 {
lab=R6}
N 1730 -350 1730 -270 {
lab=R6}
N 210 -240 210 -190 {
lab=IM}
N 230 -230 230 -190 {
lab=IM_T}
N 250 -220 250 -190 {
lab=VDD}
N 330 -210 330 -140 {
lab=IOUT+}
N 330 -120 340 -120 {
lab=IOUT-}
N 340 -200 340 -120 {
lab=IOUT-}
N 490 -240 490 -190 {
lab=IM}
N 510 -230 510 -190 {
lab=IM_T}
N 530 -220 530 -190 {
lab=VDD}
N 610 -210 610 -140 {
lab=IOUT+}
N 610 -120 630 -120 {
lab=IOUT-}
N 630 -200 630 -120 {
lab=IOUT-}
N 750 -240 750 -190 {
lab=IM}
N 770 -230 770 -190 {
lab=IM_T}
N 790 -220 790 -190 {
lab=VDD}
N 870 -210 870 -140 {
lab=IOUT+}
N 880 -200 880 -120 {
lab=IOUT-}
N 870 -120 880 -120 {
lab=IOUT-}
N 1030 -240 1030 -190 {
lab=IM}
N 1050 -230 1050 -190 {
lab=IM_T}
N 1070 -220 1070 -190 {
lab=VDD}
N 1150 -210 1150 -140 {
lab=IOUT+}
N 1150 -120 1160 -120 {
lab=IOUT-}
N 1160 -200 1160 -120 {
lab=IOUT-}
N 1290 -240 1290 -190 {
lab=IM}
N 1310 -230 1310 -190 {
lab=IM_T}
N 1330 -220 1330 -190 {
lab=VDD}
N 1410 -210 1410 -140 {
lab=IOUT+}
N 1420 -200 1420 -120 {
lab=IOUT-}
N 1410 -120 1420 -120 {
lab=IOUT-}
N 1570 -240 1570 -190 {
lab=IM}
N 1590 -230 1590 -190 {
lab=IM_T}
N 1610 -220 1610 -190 {
lab=VDD}
N 1690 -210 1690 -140 {
lab=IOUT+}
N 1700 -200 1700 -120 {
lab=IOUT-}
N 1690 -120 1700 -120 {
lab=IOUT-}
N 1830 -240 1830 -190 {
lab=IM}
N 1850 -230 1850 -190 {
lab=IM_T}
N 1870 -220 1870 -190 {
lab=VDD}
N 1950 -210 1950 -140 {
lab=IOUT+}
N 1950 -120 1960 -120 {
lab=IOUT-}
N 1960 -200 1960 -120 {
lab=IOUT-}
N 120 -130 150 -130 {
lab=VSS}
N 120 -130 120 -50 {
lab=VSS}
N 110 -150 110 -40 {
lab=R6}
N 110 -150 150 -150 {
lab=R6}
N 380 -150 430 -150 {
lab=R6}
N 380 -150 380 -40 {
lab=R6}
N 390 -130 390 -50 {
lab=VSS}
N 390 -130 430 -130 {
lab=VSS}
N 640 -150 690 -150 {
lab=R6}
N 640 -150 640 -40 {
lab=R6}
N 650 -130 690 -130 {
lab=VSS}
N 650 -130 650 -50 {
lab=VSS}
N 910 -150 970 -150 {
lab=R6}
N 910 -150 910 -40 {
lab=R6}
N 920 -130 970 -130 {
lab=VSS}
N 920 -130 920 -50 {
lab=VSS}
N 1180 -150 1230 -150 {
lab=R6}
N 1180 -150 1180 -40 {
lab=R6}
N 1190 -130 1230 -130 {
lab=VSS}
N 1190 -130 1190 -50 {
lab=VSS}
N 1450 -150 1510 -150 {
lab=R6}
N 1450 -150 1450 -40 {
lab=R6}
N 1460 -130 1510 -130 {
lab=VSS}
N 1460 -130 1460 -50 {
lab=VSS}
N 1720 -150 1770 -150 {
lab=R6}
N 1720 -150 1720 -40 {
lab=R6}
N 1730 -130 1770 -130 {
lab=VSS}
N 1730 -130 1730 -50 {
lab=VSS}
N 130 -1650 150 -1650 {
lab=C0}
N 130 -1650 130 -110 {
lab=C0}
N 130 -330 150 -330 {
lab=C0}
N 130 -550 150 -550 {
lab=C0}
N 130 -770 150 -770 {
lab=C0}
N 130 -990 150 -990 {
lab=C0}
N 130 -1210 150 -1210 {
lab=C0}
N 130 -1430 150 -1430 {
lab=C0}
N 400 -1650 430 -1650 {
lab=C1}
N 400 -1650 400 -110 {
lab=C1}
N 400 -110 430 -110 {
lab=C1}
N 660 -110 690 -110 {
lab=C2}
N 660 -1650 660 -110 {
lab=C2}
N 660 -1650 690 -1650 {
lab=C2}
N 930 -1650 970 -1650 {
lab=C3}
N 930 -1650 930 -110 {
lab=C3}
N 930 -110 970 -110 {
lab=C3}
N 1200 -110 1230 -110 {
lab=C4}
N 1200 -1650 1200 -110 {
lab=C4}
N 1200 -1650 1230 -1650 {
lab=C4}
N 1470 -1650 1510 -1650 {
lab=C5}
N 1470 -1650 1470 -110 {
lab=C5}
N 1470 -110 1510 -110 {
lab=C5}
N 1740 -110 1770 -110 {
lab=C6}
N 1740 -1650 1740 -110 {
lab=C6}
N 1740 -1650 1770 -1650 {
lab=C6}
N 2020 -1650 2050 -1650 {
lab=VSS}
N 2020 -330 2050 -330 {
lab=VSS}
N 2020 -550 2050 -550 {
lab=VSS}
N 1740 -550 1770 -550 {
lab=C6}
N 1740 -330 1770 -330 {
lab=C6}
N 1470 -330 1510 -330 {
lab=C5}
N 2020 -1430 2050 -1430 {
lab=VSS}
N 1740 -1430 1770 -1430 {
lab=C6}
N 1470 -1430 1510 -1430 {
lab=C5}
N 1200 -1430 1230 -1430 {
lab=C4}
N 930 -1430 970 -1430 {
lab=C3}
N 660 -1430 690 -1430 {
lab=C2}
N 400 -1430 430 -1430 {
lab=C1}
N 400 -1210 430 -1210 {
lab=C1}
N 660 -1210 690 -1210 {
lab=C2}
N 930 -1210 970 -1210 {
lab=C3}
N 1470 -1210 1510 -1210 {
lab=C5}
N 1200 -1210 1230 -1210 {
lab=C4}
N 1740 -1210 1770 -1210 {
lab=C6}
N 2010 -1210 2050 -1210 {
lab=R2}
N 2020 -990 2050 -990 {
lab=VSS}
N 1740 -990 1770 -990 {
lab=C6}
N 1470 -990 1510 -990 {
lab=C5}
N 1200 -990 1230 -990 {
lab=C4}
N 930 -990 970 -990 {
lab=C3}
N 660 -990 690 -990 {
lab=C2}
N 400 -990 430 -990 {
lab=C1}
N 400 -770 430 -770 {
lab=C1}
N 660 -770 690 -770 {
lab=C2}
N 930 -770 970 -770 {
lab=C3}
N 1200 -770 1230 -770 {
lab=C4}
N 1470 -770 1510 -770 {
lab=C5}
N 1740 -770 1770 -770 {
lab=C6}
N 2020 -770 2050 -770 {
lab=VSS}
N 1470 -550 1510 -550 {
lab=C5}
N 1200 -550 1230 -550 {
lab=C4}
N 930 -550 970 -550 {
lab=C3}
N 660 -550 690 -550 {
lab=C2}
N 400 -550 430 -550 {
lab=C1}
N 400 -330 430 -330 {
lab=C1}
N 680 -330 690 -330 {
lab=C2}
N 660 -330 680 -330 {
lab=C2}
N 930 -330 970 -330 {
lab=C3}
N 1200 -330 1230 -330 {
lab=C4}
N 230 -60 1850 -60 {
lab=VSS}
N 120 -50 1730 -50 {
lab=VSS}
N 110 -40 1720 -40 {
lab=R6}
N 210 -240 1830 -240 {
lab=IM}
N 230 -230 1850 -230 {
lab=IM_T}
N 250 -220 1870 -220 {
lab=VDD}
N 330 -210 1950 -210 {
lab=IOUT+}
N 340 -200 1960 -200 {
lab=IOUT-}
N 2020 -1650 2020 -330 {
lab=VSS}
N 2150 -1540 2510 -1540 {
lab=VDD}
N 2510 -1540 2510 -1490 {
lab=VDD}
N 2510 -1490 2900 -1490 {
lab=VDD}
N 2510 -1310 2900 -1310 {
lab=VSS}
N 2320 -1310 2510 -1310 {
lab=VSS}
N 2320 -1380 2320 -1310 {
lab=VSS}
N 2130 -1380 2320 -1380 {
lab=VSS}
N 2360 -1420 2400 -1420 {
lab=B9}
N 2360 -1400 2400 -1400 {
lab=B8}
N 2360 -1380 2400 -1380 {
lab=B7}
N 2750 -1420 2790 -1420 {
lab=B12}
N 2750 -1400 2790 -1400 {
lab=B11}
N 2750 -1380 2790 -1380 {
lab=B10}
N 2630 -1460 2670 -1460 {
lab=C6}
N 2630 -1440 2670 -1440 {
lab=C5}
N 2630 -1420 2640 -1420 {
lab=C4}
N 2640 -1420 2670 -1420 {
lab=C4}
N 2630 -1400 2670 -1400 {
lab=C3}
N 2630 -1380 2670 -1380 {
lab=C2}
N 2630 -1340 2670 -1340 {
lab=C0}
N 3020 -1460 3060 -1460 {
lab=R6}
N 3020 -1440 3060 -1440 {
lab=R5}
N 3020 -1420 3030 -1420 {
lab=R4}
N 3030 -1420 3060 -1420 {
lab=R4}
N 3020 -1400 3060 -1400 {
lab=R3}
N 3020 -1380 3060 -1380 {
lab=R2}
N 3020 -1360 3060 -1360 {
lab=R1}
N 3020 -1340 3060 -1340 {
lab=R0}
N 2700 -1240 2740 -1240 {
lab=IM_T}
N 2700 -1240 2700 -1210 {
lab=IM_T}
N 2700 -1130 2740 -1130 {
lab=IM}
N 2700 -1130 2700 -1100 {
lab=IM}
N 2740 -1180 2740 -1130 {
lab=IM}
N 2740 -1210 2760 -1210 {
lab=VSS}
N 2760 -1210 2760 -1070 {
lab=VSS}
N 2740 -1070 2760 -1070 {
lab=VSS}
N 2740 -1100 2760 -1100 {
lab=VSS}
N 2630 -1360 2670 -1360 {
lab=C1}
N 130 -110 150 -110 {
lab=C0}
C {devices/lab_pin.sym} 210 -1780 0 0 {name=p1 sig_type=std_logic lab=IM}
C {devices/lab_pin.sym} 230 -1770 0 0 {name=p2 sig_type=std_logic lab=IM_T}
C {devices/lab_pin.sym} 250 -1760 0 0 {name=p3 sig_type=std_logic lab=VDD}
C {devices/lab_pin.sym} 330 -1750 0 0 {name=p4 sig_type=std_logic lab=IOUT+}
C {devices/lab_pin.sym} 340 -1740 0 0 {name=p5 sig_type=std_logic lab=IOUT-}
C {devices/lab_pin.sym} 230 -1600 0 0 {name=p6 sig_type=std_logic lab=VSS}
C {devices/lab_pin.sym} 210 -1560 0 0 {name=p7 sig_type=std_logic lab=IM}
C {devices/lab_pin.sym} 230 -1550 0 0 {name=p8 sig_type=std_logic lab=IM_T}
C {devices/lab_pin.sym} 250 -1540 0 0 {name=p9 sig_type=std_logic lab=VDD}
C {devices/lab_pin.sym} 330 -1530 0 0 {name=p10 sig_type=std_logic lab=IOUT+}
C {devices/lab_pin.sym} 340 -1520 0 0 {name=p11 sig_type=std_logic lab=IOUT-}
C {devices/lab_pin.sym} 230 -1380 0 0 {name=p12 sig_type=std_logic lab=VSS}
C {devices/lab_pin.sym} 210 -1340 0 0 {name=p13 sig_type=std_logic lab=IM}
C {devices/lab_pin.sym} 230 -1330 0 0 {name=p14 sig_type=std_logic lab=IM_T}
C {devices/lab_pin.sym} 250 -1320 0 0 {name=p15 sig_type=std_logic lab=VDD}
C {devices/lab_pin.sym} 330 -1310 0 0 {name=p16 sig_type=std_logic lab=IOUT+}
C {devices/lab_pin.sym} 340 -1300 0 0 {name=p17 sig_type=std_logic lab=IOUT-}
C {devices/lab_pin.sym} 230 -1160 0 0 {name=p18 sig_type=std_logic lab=VSS}
C {devices/lab_pin.sym} 210 -1120 0 0 {name=p19 sig_type=std_logic lab=IM}
C {devices/lab_pin.sym} 230 -1110 0 0 {name=p20 sig_type=std_logic lab=IM_T}
C {devices/lab_pin.sym} 250 -1100 0 0 {name=p21 sig_type=std_logic lab=VDD}
C {devices/lab_pin.sym} 330 -1090 0 0 {name=p22 sig_type=std_logic lab=IOUT+}
C {devices/lab_pin.sym} 340 -1080 0 0 {name=p23 sig_type=std_logic lab=IOUT-}
C {devices/lab_pin.sym} 230 -940 0 0 {name=p24 sig_type=std_logic lab=VSS}
C {devices/lab_pin.sym} 210 -900 0 0 {name=p25 sig_type=std_logic lab=IM}
C {devices/lab_pin.sym} 230 -890 0 0 {name=p26 sig_type=std_logic lab=IM_T}
C {devices/lab_pin.sym} 250 -880 0 0 {name=p27 sig_type=std_logic lab=VDD}
C {devices/lab_pin.sym} 330 -870 0 0 {name=p28 sig_type=std_logic lab=IOUT+}
C {devices/lab_pin.sym} 340 -860 0 0 {name=p29 sig_type=std_logic lab=IOUT-}
C {devices/lab_pin.sym} 230 -720 0 0 {name=p30 sig_type=std_logic lab=VSS}
C {devices/lab_pin.sym} 210 -680 0 0 {name=p31 sig_type=std_logic lab=IM}
C {devices/lab_pin.sym} 230 -670 0 0 {name=p32 sig_type=std_logic lab=IM_T}
C {devices/lab_pin.sym} 250 -660 0 0 {name=p33 sig_type=std_logic lab=VDD}
C {devices/lab_pin.sym} 330 -650 0 0 {name=p34 sig_type=std_logic lab=IOUT+}
C {devices/lab_pin.sym} 340 -640 0 0 {name=p35 sig_type=std_logic lab=IOUT-}
C {devices/lab_pin.sym} 230 -500 0 0 {name=p36 sig_type=std_logic lab=VSS}
C {devices/lab_pin.sym} 210 -460 0 0 {name=p37 sig_type=std_logic lab=IM}
C {devices/lab_pin.sym} 230 -450 0 0 {name=p38 sig_type=std_logic lab=IM_T}
C {devices/lab_pin.sym} 250 -440 0 0 {name=p39 sig_type=std_logic lab=VDD}
C {devices/lab_pin.sym} 330 -430 0 0 {name=p40 sig_type=std_logic lab=IOUT+}
C {devices/lab_pin.sym} 340 -420 0 0 {name=p41 sig_type=std_logic lab=IOUT-}
C {devices/lab_pin.sym} 230 -280 0 0 {name=p42 sig_type=std_logic lab=VSS}
C {devices/lab_pin.sym} 210 -240 0 0 {name=p43 sig_type=std_logic lab=IM}
C {devices/lab_pin.sym} 230 -230 0 0 {name=p44 sig_type=std_logic lab=IM_T}
C {devices/lab_pin.sym} 250 -220 0 0 {name=p45 sig_type=std_logic lab=VDD}
C {devices/lab_pin.sym} 330 -210 0 0 {name=p46 sig_type=std_logic lab=IOUT+}
C {devices/lab_pin.sym} 340 -200 0 0 {name=p47 sig_type=std_logic lab=IOUT-}
C {devices/lab_pin.sym} 230 -60 0 0 {name=p48 sig_type=std_logic lab=VSS}
C {devices/lab_pin.sym} 110 -1690 0 0 {name=p49 sig_type=std_logic lab=VDD}
C {devices/lab_pin.sym} 120 -1670 0 0 {name=p50 sig_type=std_logic lab=R0}
C {devices/lab_pin.sym} 130 -1650 0 0 {name=p51 sig_type=std_logic lab=C0}
C {devices/lab_pin.sym} 110 -1470 0 0 {name=p52 sig_type=std_logic lab=R0}
C {devices/lab_pin.sym} 400 -1650 0 0 {name=p53 sig_type=std_logic lab=C1}
C {devices/lab_pin.sym} 660 -1650 0 0 {name=p54 sig_type=std_logic lab=C2}
C {devices/lab_pin.sym} 930 -1650 0 0 {name=p55 sig_type=std_logic lab=C3}
C {devices/lab_pin.sym} 1200 -1650 0 0 {name=p56 sig_type=std_logic lab=C4}
C {devices/lab_pin.sym} 1470 -1650 0 0 {name=p57 sig_type=std_logic lab=C5}
C {devices/lab_pin.sym} 1740 -1650 0 0 {name=p58 sig_type=std_logic lab=C6}
C {devices/lab_pin.sym} 2020 -1650 0 0 {name=p59 sig_type=std_logic lab=VSS}
C {devices/lab_pin.sym} 120 -1450 0 0 {name=p60 sig_type=std_logic lab=R1}
C {devices/lab_pin.sym} 110 -1250 0 0 {name=p61 sig_type=std_logic lab=R1}
C {devices/lab_pin.sym} 120 -1230 0 0 {name=p62 sig_type=std_logic lab=R2}
C {devices/lab_pin.sym} 110 -1030 0 0 {name=p63 sig_type=std_logic lab=R2}
C {devices/lab_pin.sym} 120 -1010 0 0 {name=p64 sig_type=std_logic lab=R3}
C {devices/lab_pin.sym} 110 -810 0 0 {name=p65 sig_type=std_logic lab=R3}
C {devices/lab_pin.sym} 120 -790 0 0 {name=p66 sig_type=std_logic lab=R4}
C {devices/lab_pin.sym} 110 -590 0 0 {name=p67 sig_type=std_logic lab=R4}
C {devices/lab_pin.sym} 120 -570 0 0 {name=p68 sig_type=std_logic lab=R5}
C {devices/lab_pin.sym} 110 -370 0 0 {name=p69 sig_type=std_logic lab=R5}
C {devices/lab_pin.sym} 120 -350 0 0 {name=p70 sig_type=std_logic lab=R6}
C {devices/lab_pin.sym} 110 -150 0 0 {name=p71 sig_type=std_logic lab=R6}
C {devices/lab_pin.sym} 120 -130 0 0 {name=p72 sig_type=std_logic lab=VSS}
C {Thermo_Decoder.sym} 2880 -1380 0 0 {name=x65}
C {devices/lab_pin.sym} 2680 -1490 0 0 {name=p73 sig_type=std_logic lab=VDD}
C {devices/lab_pin.sym} 2700 -1310 0 0 {name=p74 sig_type=std_logic lab=VSS}
C {devices/lab_pin.sym} 2670 -1460 0 0 {name=p76 sig_type=std_logic lab=C6}
C {devices/lab_pin.sym} 2670 -1440 0 0 {name=p78 sig_type=std_logic lab=C5}
C {devices/lab_pin.sym} 2670 -1420 0 0 {name=p80 sig_type=std_logic lab=C4}
C {devices/lab_pin.sym} 2670 -1400 0 0 {name=p82 sig_type=std_logic lab=C3}
C {devices/lab_pin.sym} 2670 -1380 0 0 {name=p84 sig_type=std_logic lab=C2}
C {devices/lab_pin.sym} 2670 -1360 0 0 {name=p86 sig_type=std_logic lab=C1}
C {devices/lab_pin.sym} 2670 -1340 0 0 {name=p88 sig_type=std_logic lab=C0}
C {devices/lab_pin.sym} 3060 -1460 0 0 {name=p79 sig_type=std_logic lab=R6}
C {devices/lab_pin.sym} 3060 -1440 0 0 {name=p81 sig_type=std_logic lab=R5}
C {devices/lab_pin.sym} 3060 -1420 0 0 {name=p83 sig_type=std_logic lab=R4}
C {devices/lab_pin.sym} 3060 -1400 0 0 {name=p85 sig_type=std_logic lab=R3}
C {devices/lab_pin.sym} 3060 -1380 0 0 {name=p87 sig_type=std_logic lab=R2}
C {devices/lab_pin.sym} 3060 -1360 0 0 {name=p89 sig_type=std_logic lab=R1}
C {devices/lab_pin.sym} 3060 -1340 0 0 {name=p90 sig_type=std_logic lab=R0}
C {devices/lab_pin.sym} 2360 -1420 0 0 {name=p91 sig_type=std_logic lab=B9}
C {devices/lab_pin.sym} 2360 -1400 0 0 {name=p92 sig_type=std_logic lab=B8}
C {devices/lab_pin.sym} 2360 -1380 0 0 {name=p93 sig_type=std_logic lab=B7}
C {devices/lab_pin.sym} 2750 -1420 0 0 {name=p94 sig_type=std_logic lab=B12}
C {devices/lab_pin.sym} 2750 -1400 0 0 {name=p95 sig_type=std_logic lab=B11}
C {devices/lab_pin.sym} 2750 -1380 0 0 {name=p96 sig_type=std_logic lab=B10}
C {devices/iopin.sym} 2370 -1240 0 0 {name=p97 lab=VDD}
C {devices/iopin.sym} 2460 -1240 0 0 {name=p98 lab=VSS}
C {devices/ipin.sym} 2420 -1200 0 0 {name=p99 lab=B7}
C {devices/ipin.sym} 2510 -1200 0 0 {name=p100 lab=B11}
C {devices/ipin.sym} 2420 -1170 0 0 {name=p101 lab=B8}
C {devices/ipin.sym} 2510 -1170 0 0 {name=p102 lab=B12}
C {devices/ipin.sym} 2420 -1140 0 0 {name=p103 lab=B9}
C {devices/ipin.sym} 2510 -1140 0 0 {name=p104 lab=IM_T}
C {devices/ipin.sym} 2420 -1110 0 0 {name=p105 lab=B10}
C {devices/opin.sym} 2370 -1070 0 0 {name=p106 lab=IOUT+}
C {devices/opin.sym} 2460 -1070 0 0 {name=p107 lab=IOUT-}
C {symbols/nfet_03v3.sym} 2720 -1210 0 0 {name=M1
L=0.28u
W=0.5u
nf=1
m=1
ad="'int((nf+1)/2) * W/nf * 0.18u'"
pd="'2*int((nf+1)/2) * (W/nf + 0.18u)'"
as="'int((nf+2)/2) * W/nf * 0.18u'"
ps="'2*int((nf+2)/2) * (W/nf + 0.18u)'"
nrd="'0.18u / W'" nrs="'0.18u / W'"
sa=0 sb=0 sd=0
model=nfet_03v3
spiceprefix=X
}
C {symbols/nfet_03v3.sym} 2720 -1100 0 0 {name=M2
L=0.28u
W=0.5u
nf=1
m=1
ad="'int((nf+1)/2) * W/nf * 0.18u'"
pd="'2*int((nf+1)/2) * (W/nf + 0.18u)'"
as="'int((nf+2)/2) * W/nf * 0.18u'"
ps="'2*int((nf+2)/2) * (W/nf + 0.18u)'"
nrd="'0.18u / W'" nrs="'0.18u / W'"
sa=0 sb=0 sd=0
model=nfet_03v3
spiceprefix=X
}
C {devices/lab_pin.sym} 2760 -1160 0 0 {name=p108 sig_type=std_logic lab=VSS}
C {devices/lab_pin.sym} 2700 -1240 0 0 {name=p109 sig_type=std_logic lab=IM_T}
C {devices/lab_pin.sym} 2700 -1130 0 0 {name=p110 sig_type=std_logic lab=IM}
C {Thermo_Decoder.sym} 2490 -1380 0 0 {name=x56}
C {MSB_UNIT_CELL_V3.sym} 230 -1660 0 0 {name=x1}
C {MSB_UNIT_CELL_V3.sym} 510 -1660 0 0 {name=x2}
C {MSB_UNIT_CELL_V3.sym} 770 -1660 0 0 {name=x3}
C {MSB_UNIT_CELL_V3.sym} 1050 -1660 0 0 {name=x4}
C {MSB_UNIT_CELL_V3.sym} 1310 -1660 0 0 {name=x5}
C {MSB_UNIT_CELL_V3.sym} 1590 -1660 0 0 {name=x6}
C {MSB_UNIT_CELL_V3.sym} 1850 -1660 0 0 {name=x7}
C {MSB_UNIT_CELL_V3.sym} 2130 -1660 0 0 {name=x8}
C {MSB_UNIT_CELL_V3.sym} 230 -1440 0 0 {name=x9}
C {MSB_UNIT_CELL_V3.sym} 510 -1440 0 0 {name=x10}
C {MSB_UNIT_CELL_V3.sym} 770 -1440 0 0 {name=x11}
C {MSB_UNIT_CELL_V3.sym} 1050 -1440 0 0 {name=x12}
C {MSB_UNIT_CELL_V3.sym} 1310 -1440 0 0 {name=x13}
C {MSB_UNIT_CELL_V3.sym} 1590 -1440 0 0 {name=x14}
C {MSB_UNIT_CELL_V3.sym} 1850 -1440 0 0 {name=x15}
C {MSB_UNIT_CELL_V3.sym} 2130 -1440 0 0 {name=x16}
C {MSB_UNIT_CELL_V3.sym} 230 -1220 0 0 {name=x17}
C {MSB_UNIT_CELL_V3.sym} 510 -1220 0 0 {name=x18}
C {MSB_UNIT_CELL_V3.sym} 770 -1220 0 0 {name=x19}
C {MSB_UNIT_CELL_V3.sym} 1050 -1220 0 0 {name=x20}
C {MSB_UNIT_CELL_V3.sym} 1310 -1220 0 0 {name=x21}
C {MSB_UNIT_CELL_V3.sym} 1590 -1220 0 0 {name=x22}
C {MSB_UNIT_CELL_V3.sym} 1850 -1220 0 0 {name=x23}
C {MSB_UNIT_CELL_V3.sym} 2130 -1220 0 0 {name=x24}
C {MSB_UNIT_CELL_V3.sym} 230 -1000 0 0 {name=x25}
C {MSB_UNIT_CELL_V3.sym} 510 -1000 0 0 {name=x26}
C {MSB_UNIT_CELL_V3.sym} 770 -1000 0 0 {name=x27}
C {MSB_UNIT_CELL_V3.sym} 1050 -1000 0 0 {name=x28}
C {MSB_UNIT_CELL_V3.sym} 1310 -1000 0 0 {name=x29}
C {MSB_UNIT_CELL_V3.sym} 1590 -1000 0 0 {name=x30}
C {MSB_UNIT_CELL_V3.sym} 1850 -1000 0 0 {name=x31}
C {MSB_UNIT_CELL_V3.sym} 2130 -1000 0 0 {name=x32}
C {MSB_UNIT_CELL_V3.sym} 230 -780 0 0 {name=x33}
C {MSB_UNIT_CELL_V3.sym} 510 -780 0 0 {name=x34}
C {MSB_UNIT_CELL_V3.sym} 770 -780 0 0 {name=x35}
C {MSB_UNIT_CELL_V3.sym} 1050 -780 0 0 {name=x36}
C {MSB_UNIT_CELL_V3.sym} 1310 -780 0 0 {name=x37}
C {MSB_UNIT_CELL_V3.sym} 1590 -780 0 0 {name=x38}
C {MSB_UNIT_CELL_V3.sym} 1850 -780 0 0 {name=x39}
C {MSB_UNIT_CELL_V3.sym} 2130 -780 0 0 {name=x40}
C {MSB_UNIT_CELL_V3.sym} 230 -560 0 0 {name=x41}
C {MSB_UNIT_CELL_V3.sym} 510 -560 0 0 {name=x42}
C {MSB_UNIT_CELL_V3.sym} 770 -560 0 0 {name=x43}
C {MSB_UNIT_CELL_V3.sym} 1050 -560 0 0 {name=x44}
C {MSB_UNIT_CELL_V3.sym} 1310 -560 0 0 {name=x45}
C {MSB_UNIT_CELL_V3.sym} 1590 -560 0 0 {name=x46}
C {MSB_UNIT_CELL_V3.sym} 1850 -560 0 0 {name=x47}
C {MSB_UNIT_CELL_V3.sym} 2130 -560 0 0 {name=x48}
C {MSB_UNIT_CELL_V3.sym} 230 -340 0 0 {name=x49}
C {MSB_UNIT_CELL_V3.sym} 510 -340 0 0 {name=x50}
C {MSB_UNIT_CELL_V3.sym} 770 -340 0 0 {name=x51}
C {MSB_UNIT_CELL_V3.sym} 1050 -340 0 0 {name=x52}
C {MSB_UNIT_CELL_V3.sym} 1310 -340 0 0 {name=x53}
C {MSB_UNIT_CELL_V3.sym} 1590 -340 0 0 {name=x54}
C {MSB_UNIT_CELL_V3.sym} 1850 -340 0 0 {name=x55}
C {MSB_UNIT_CELL_V3.sym} 2130 -340 0 0 {name=x57}
C {MSB_UNIT_CELL_V3.sym} 230 -120 0 0 {name=x58}
C {MSB_UNIT_CELL_V3.sym} 510 -120 0 0 {name=x59}
C {MSB_UNIT_CELL_V3.sym} 770 -120 0 0 {name=x60}
C {MSB_UNIT_CELL_V3.sym} 1050 -120 0 0 {name=x61}
C {MSB_UNIT_CELL_V3.sym} 1310 -120 0 0 {name=x62}
C {MSB_UNIT_CELL_V3.sym} 1590 -120 0 0 {name=x63}
C {MSB_UNIT_CELL_V3.sym} 1850 -120 0 0 {name=x64}
